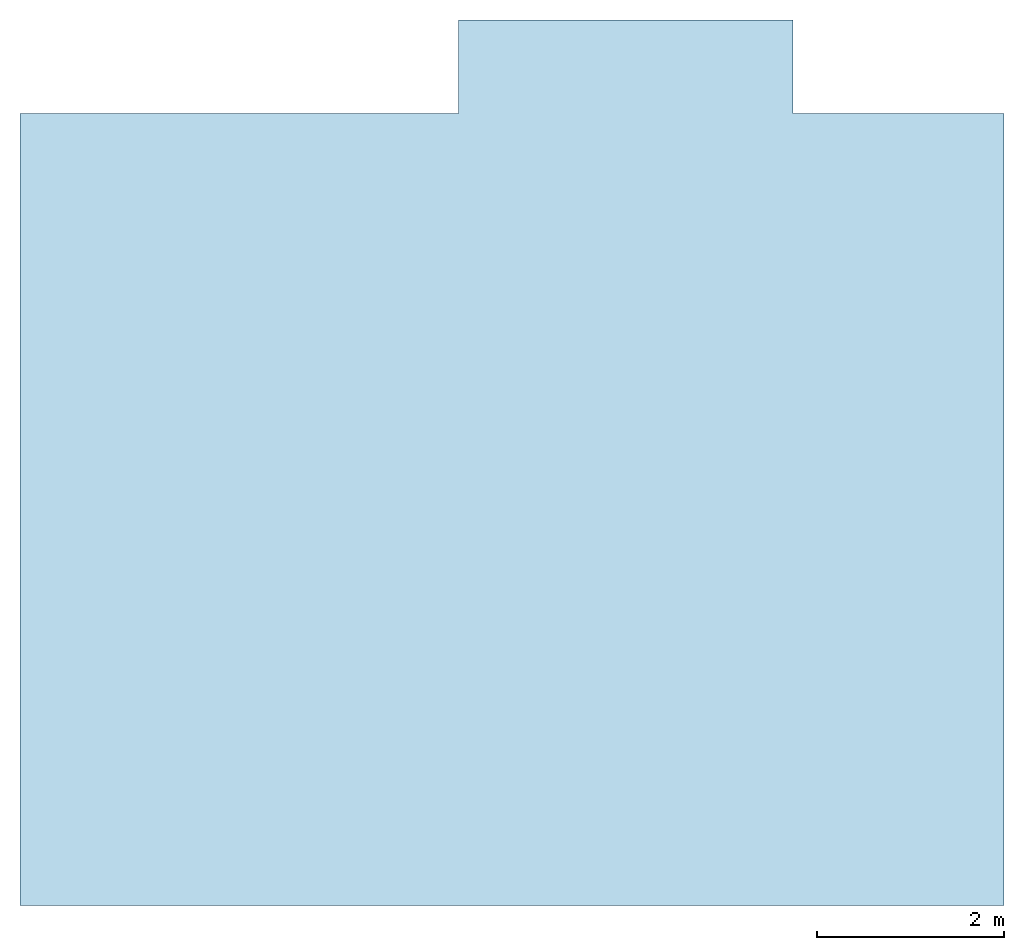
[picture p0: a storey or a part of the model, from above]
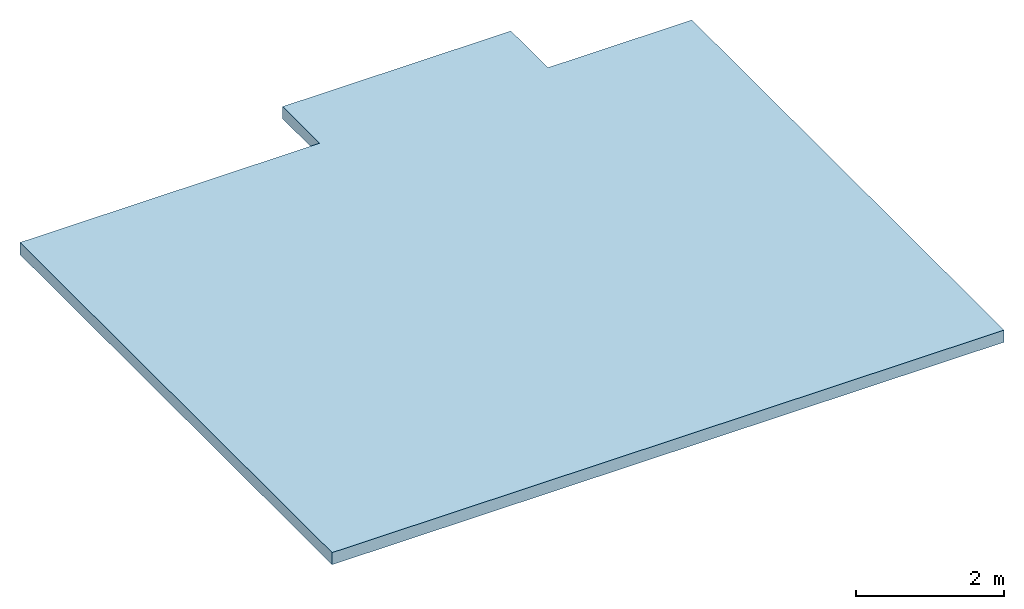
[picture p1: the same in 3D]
Properties of the parts of a building model (IFC2X3), part 6 of 6

# IfcWindow: Janela Multi-Caixilho Vertical 27 (3)
BaseQuantities - GrossArea: 0.64 m2; Height: 800 mm; Width: 800 mm; Perimeter: 3200 mm; Area: 0.64 m2; Volume: 0.0181695 m3; Depth: 160 mm; NetVolume: 0.0181695 m3
ArchiCADQuantities - Abertura Volume de Vão L/D: 0.10444 m3; P/J Volume Nominal da Abertura: 0.1024 m3; Abertura Área da Superfície L/D: 2.73291 m2; P/J Área de Superfície Nominal do Vão: 0.64 m2; P/J Largura do Vão no Lado Oposto do Requadro: 800 mm; P/J Altura do Vão no Lado Oposto do Requadro: 830 mm; P/J Largura do Vão no Lado do Requadro: 800 mm; P/J Altura do Vão no Lado do Requadro: 800 mm; Área da Superfície da Abertura no Lado do Requadro da J/P: 0.664 m2; Área da Superfície da Abertura no Lado Oposto ao Requadro da J/P: 0.64 m2; P/J Largura do Vão Nominal no Lado Oposto do Requadro: 800 mm; P/J Altura do Vão Nominal no Lado Oposto do Requadro: 800 mm; P/J Largura do Vão Nominal no Lado do Requadro: 800 mm; P/J Altura do Vão Nominal no Lado do Requadro: 800 mm; P/J Área da Superfície do Vão Nominal no Lado do Requadro: 0.64 m2; P/J Área da Superfície do Vão Nominal no Lado Oposto do Requadro: 0.64 m2; Altura da Soleira/Peitoril ou Padieira: 1400 mm; P/J Altura Nominal do Parapeito: 1400 mm; P/J Altura do Parapeito no Lado do Requadro: 1400 mm; P/J Altura do Parapeito no Lado Oposto do Requadro: 1400 mm; P/J Altura Nominal da Padieira: 2200 mm; P/J Altura da Padiera no Lado Oposto do Requadro: 2200 mm; P/J Altura da Padiera no Lado do Requadro: 2200 mm; Espessura da Parede: 160 mm; Espessura do Batente: 50 mm; Altura: 800 mm; Volume (Líquido): 0.0181695 m3; Largura: 800 mm; Elevação à Origem do Projeto: 1400 mm; Elevação ao 1º Nível de Referência: 1400 mm; Elevação ao 2º Nível de Referência: 1400 mm; Elevação ao Nível do Mar: 1400 mm; Elevação ao Piso: 1400 mm; Afastamento do Piso de Origem: 1400 mm; Área da Superfície: 2.73291 m2; Elevação do Topo ao Primeiro Nível de Referência: 2200 mm; Elevação do Topo Ao Piso de Origem: 2200 mm; Elevação do Topo À Cota Zero: 2200 mm; Elevação do Topo Ao Nível do Mar: 2200 mm; Elevação do Topo Ao Segundo Nível de Referência: 2200 mm; Elevação da Base Ao Primeiro Nível de Referência: 1370 mm; Elevação da Base Ao Piso de Origem: 1370 mm; Elevação da Base À Cota Zero: 1370 mm; Elevação da Base Ao Nível do Mar: 1370 mm; Elevação da Base Ao Segundo Nível de Referência: 1370 mm; Área da Superfície da Base (Líquida): 2.73291 m2
AC_Equantity_Janela_Multi-Caixilho_Vertical_27 - Largura: 800 mm; Altura: 800 mm; Dimensão Z: 1000 mm; Nível da Base: 1000 mm; Nível do Topo: 0 mm; Altura Peitoril ao Piso Atual: 1400 mm; Abertura para o Núcleo da Parede: 50 mm; Nova Largura Direita da Trama de Parede: 150 mm; Nova Largura Esquerda da Trama de Parede: 150 mm; Espessura Parede Ligação: 0 mm; Espessura Parede 2 Conectada: 160 mm; Espessura Parede 1 Conectada: 160 mm; Largura Pilar de Canto: 0 mm; Espessura Pilar Canto: 0 mm; Projeção Pilar de Canto: 0 mm; Tolerância Máxima: 100 mm; Tolerância: 0 mm; Tolerância Esquerda: 0 mm; Tolerância Direita: 0 mm; Tolerância Superior: 0 mm; Tolerância Inferior: 0 mm; Largura de Vão: 800 mm; Altura de Vão: 800 mm; Largura Face de Vão: 800 mm; Altura Face de Vão: 800 mm; Largura Unidade: 800 mm; Altura Unidade: 800 mm; Distância Eixo: 800 mm; Altura Painel 1: 212.5 mm; Altura Painel 2: 187.5 mm; Altura Painel 3: 187.5 mm; Altura Painel 4: 212.5 mm; Altura Painel 5: 256 mm; Altura Painel 6: 500 mm; Altura Painel 7: 500 mm; Altura Painel 8: 500 mm; Altura Painel 9: 500 mm; Altura do Painel Restante: 307 mm; Espessura Batente: 50 mm; Largura Batente: 50 mm; Largura Batente Lado 2: 47 mm; Largura Batente Cimo: 47 mm; Largura Batente Base: 47 mm; Profundidade Rebaixo: 20 mm; Largura Rebaixo: 20 mm; Largura Bandeira centro: 80 mm; Largura Bandeira 1: 100 mm; Largura Bandeira 2: 100 mm; Largura Bandeira 3: 100 mm; Largura Bandeira 4: 100 mm; Largura Bandeira 5: 100 mm; Largura Bandeira 6: 100 mm; Largura Bandeira 7: 100 mm; Largura Bandeira 8: 100 mm; Largura Bandeira 9: 100 mm; Altura das Divisões Horizontais do Caixilho 1: 117.5 mm; Altura das Divisões Horizontais do Caixilho 2: 117.5 mm; Altura das Divisões Horizontais do Caixilho 3: 117.5 mm; Altura das Divisões Horizontais do Caixilho 4: 117.5 mm; Altura das Divisões Horizontais do Caixilho 5: 176 mm; Altura das Divisões Horizontais do Caixilho 6: 900 mm; Altura das Divisões Horizontais do Caixilho 7: 900 mm; Altura das Divisões Horizontais do Caixilho 8: 900 mm; Altura das Divisões Horizontais do Caixilho 9: 900 mm; Altura das Divisões Horizontais do Caixilho 10: 900 mm; Espessura Estrutura Caixilho: 20 mm; Largura Caixilho: 50 mm; Largura Grelha: 20 mm; Espessura Grelha: 25 mm; Espessura Vidro: 20 mm; Espessura Venezianas: 10 mm; Largura Venezianas: 50 mm; Sobred. Abertura Esquerda: 0 mm; Sobred. Direita Abertura: 0 mm; Sobred. Topo Abertura: 0 mm; Sobred. Base Abertura: 0 mm; Largura Arquitrave Principal: 20 mm; Largura Lado 1 (gs_tw_right_out): 100 mm; Largura Lado 2 (gs_tw_left_out): 100 mm; Largura Topo (gs_tw_top_out): 100 mm; Largura Inferior (gs_tw_bottom_out): 100 mm; Espessura de Parede (gs_trim_thk_out): 25 mm; Espessura na Abertura da Parede (gs_trim_width_out): 25 mm; Paralelas (gs_trim_offs_out): 0 mm; Bordo (gs_trim_jambext_nosing_out): 50 mm; Saliência Superior (gs_trimov_top_left_out): 0 mm; Saliência Superior (gs_trimov_top_right_out): 0 mm; Ressalto Inferior (gs_trimov_bot_left_out): 0 mm; Ressalto Inferior (gs_trimov_bot_right_out): 0 mm; Ressalto Inferior (casingOverhangBottomSideOut): 50 mm; Largura Lado 1 (gs_tw_right_in): 100 mm; Largura Lado 2 (gs_tw_left_in): 100 mm; Largura Topo (gs_tw_top_in): 100 mm; Largura Inferior (gs_tw_bottom_in): 100 mm; Espessura de Parede (gs_trim_thk_in): 25 mm; Espessura na Abertura da Parede (gs_trim_width_in): 25 mm; Paralelas (gs_trim_offs_in): 0 mm; Bordo (gs_trim_jambext_nosing_in): 50 mm; Saliência Superior (gs_trimov_top_left_in): 0 mm; Saliência Superior (gs_trimov_top_right_in): 0 mm; Ressalto Inferior (gs_trimov_bot_left_in): 0 mm; Ressalto Inferior (gs_trimov_bot_right_in): 0 mm; Largura Peitoril: 105 mm; Largura Topo Parapeito: 10 mm; Altura Topo Peitoril: 10 mm; Espessura Peitoril: 30 mm; Espessura Lateral da Frente Peitoril: 15 mm; Elevação Peitoril: 5 mm; Recobrimento Goteira Peitoril: 20 mm; Largura Goteira Peitoril: 30 mm; Testeira Peitoril: 20 mm; Avanço do Parapeito Esquerda: 0 mm; Avanço do Parapeito Direita: 0 mm; Inclinação do Parapeito: 35 mm; Inclin. Peitoril da Parede: 0 mm; Profund. Vão Posterior (gs_sill_holeDepthBehind): 0 mm; Espessura do Tijolo (gs_brick_sill_br_thk): 65 mm; Espessura de Argamassa (gs_brick_sill_mort_thk): 15 mm; Largura Peitoril Int.: 90 mm; Espessura Peitoril Int.: 25 mm; Peitoril Int. Arredondado: 30 mm; Saliência Esq. Peitoril Int.: 0 mm; Saliência Dir. Peitoril Int.: 0 mm; Inclinação do Parapeito Int.: 0 mm; Altura Perfil: 65 mm; Espessura Perfil: 110 mm; Altura Painel: 1500 mm; Afast. Interior: 20 mm; Profund. Fechamento: 0 mm; Largura Batente Extra: 40 mm; Espess. Batente Extra: 30 mm; Largura Barra:: 30 mm; Comprim. Vara Suspensa: 20 mm; Raio Vara Suspensa: 5 mm; Distância Painel: 6 mm; Saliência Exterior: 0 mm; Largura Painel Interior: 120 mm; Comprim. Abertura 3D: 1500 mm; Comprim. Fechado 3D: 0 mm; Comprimento 1 Abertura 3D (gs_shutter_opLength_1): 560 mm; Comprimento 1 Abertura 3D (gs_shutter_opLength_2): 140 mm; Altura Abertura 3D: 1500 mm; Altura Fechado 3D: 0 mm; Espessura Painel: 50 mm; Largura Estrutura Painel: 50 mm; Largura Moldura Inferior: 50 mm; Largura Painel: 0 mm; Espess. de Enchimento de Painel: 10 mm; Espessura da Veneziana: 10 mm; Largura Grelha Ventilação: 40 mm; Largura Divisor Moldura Horiz.: 50 mm; Largura de Divisor Moldura Vert.: 50 mm; Raio do Vão: 10 mm; Largura Bordo Vertical: 100 mm; Largura Estrutura Z: 50 mm; Espessura Estrutura Z: 25 mm; Espess. Placas Verticais: 25 mm; Espess. Placas Horizontais: 25 mm; Largura Aprox. Placas Verticais: 80 mm; Largura Aprox. Placas Horizontais: 115 mm; Altura Caixa (gs_shutRoll_boxHeight): 200 mm; Profund. Caixa (gs_shutRoll_boxWidth): 150 mm; Afast. Caixa Esq.: 0 mm; Afast. Caixa Dir.: 0 mm; Profund. Anteparos: 72.5 mm; Distância da Parede (gs_shutRoll_distFromWall): 0 mm; Distância da Padieira (gs_shutRoll_distFromHead): 0 mm; Largura da Ripa: 50 mm; Altura Caixa (gs_shutLam_boxHeight): 200 mm; Profund. Caixa (gs_shutLam_boxWidth): 150 mm; Largura Capa: 0 mm; Distância da Parede (gs_shutLam_distFromWall): 0 mm; Distância da Padieira (gs_shutLam_distFromHead): 0 mm; Largura Segmento (gs_shutLam_segmentWidth): 60 mm; Altura Caixa (gs_shutLam2_boxHeight): 60 mm; Largura Caixa: 60 mm; Distância da Janela: 60 mm; Distância da Padieira (gs_shutLam2_distFromHead): 60 mm; Altura do Eixo da Caixa da Padieira: 0 mm; Largura Segmento (gs_shutLam2_segmentWidth): 60 mm; Distância entre Arco e Janela: 0 mm; Avanço à Esquerda do Arco de Alvenaria: 0 mm; Avanço à Direita do Arco de Alvenaria: 0 mm; Espelho do Arco de Alvenaria: 30 mm; Projeção do Arco de Alvenaria: 0 mm; Altura do Arco de Alvenaria: 250 mm; Profundidade do Arco de Alvenaria: 120 mm; Profund. Vão Posterior (gs_masonry_arch_rearHoleDepth): 0 mm; Espessura do Tijolo (gs_masonry_arch_brick_thk): 65 mm; Espessura de Argamassa (gs_masonry_arch_mort_thk): 10 mm; Largura Fecho: 100 mm; Sobredimensão Fecho: 0 mm; Projeção Fecho: 10 mm; Profund. Face de Vão (gs_wido_sill): 50 mm; Profund. Face de Vão (AC_wido_sill): 50 mm; Profund. Ombreira Lado 2: 60 mm; Profund. Ombreira: 60 mm; Profund. Ombreira Interior Lado 2 (gs_reveal_splayed_innerLeft): 60 mm; Profund. Ombreira Interior (gs_reveal_splayed_innerRight): 60 mm; Profund. Ombreira Interior Lado 2 (gs_reveal_double_innerLeft): 60 mm; Profund. Ombreira Interior (gs_reveal_double_innerRight): 60 mm; Profund. Batente Cima: 60 mm; Profund. Batente Peitoril: 60 mm; Profundidade Padieira Interior (gs_reveal_splayed_innerTop): 60 mm; Profundidade Peitoril Interior (gs_reveal_splayed_innerBottom): 60 mm; Profundidade Padieira Interior (gs_reveal_double_innerTop): 60 mm; Profundidade Peitoril Interior (gs_reveal_double_innerBottom): 0 mm; Profund. Batente Exterior: 80 mm; Limite Espess. Reboco: 40 mm; Distância de Camada do Encerram.: 0 mm; Largura do Fecho: 38 mm; Espessura do Fecho: 100 mm; Espessura da Camada: 25 mm; Espessura do Perfil: 75 mm; Espessura Personal.: 15 mm; Saliência Camada para Espess. Batente: 0 mm; Profundidade do Recorte: 50 mm; Largura de Parapeito: 1000 mm; Avanço Lateral 1: 0 mm; Avanço Lateral 2: 0 mm; Altura Parapeito: 900 mm; Ressalto Inferior (gs_parapet_botelev): 0 mm; Distância Abertura 1 Caixilho 1: 0 mm; Distância Abertura 2 Caixilho 1: 0 mm; Distância Abertura 1 Caixilho 2: 0 mm; Distância Abertura 2 Caixilho 2: 0 mm; Distância Abertura 1 Caixilho 3: 0 mm; Distância Abertura 2 Caixilho 3: 0 mm; Distância Abertura 1 Caixilho 4: 0 mm; Distância Abertura 2 Caixilho 4: 0 mm; Distância Abertura 1 Caixilho 5: 0 mm; Distância Abertura 2 Caixilho 5: 0 mm; Distância Abertura 1 Caixilho 6: 0 mm; Distância Abertura 2 Caixilho 6: 0 mm; Distância Abertura 1 Caixilho 7: 0 mm; Distância Abertura 2 Caixilho 7: 0 mm; Distância Abertura 1 Caixilho 8: 0 mm; Distância Abertura 2 Caixilho 8: 0 mm; Distância Abertura 1 Caixilho 9: 0 mm; Distância Abertura 2 Caixilho 9: 0 mm; Distância Abertura 1 Caixilho 10: 0 mm; Distância Abertura 2 Caixilho 10: 0 mm; Comprimento Abertura em 2D: 0 mm; Sobred. Abertura Esq. AC: 0 mm; Sobred. Abertura Dir. AC: 0 mm; Sobred. Padieira AC: 0 mm; Sobred. Abertura Base AC: 0 mm
Component Quantities - Component, Volume Componente (Líquido): 0.0181695 m3; Component, Volume do componente (Bruto): 0.0181695 m3
Name | ID do Elemento = ID do Elemento e Associação | Nome da Zona Relacionada = Da Zona | Número da Zona Relacionada = Do Número de Zona
J06 | J06 | Banheiro 1 | 03
J07 | J07 | Banheiro 2 | 03
J01 | J01 | Cozinha | 05 | ArchiCADProperties - Até Zona: Cozinha; Até Número de Zona: 05

# IfcWindow: Janela de Correr 3-Caixilhos 27 (3)
In: Pavimento Térreo
Type - OperationType: USERDEFINED; ParameterTakesPrecedence: no; Sizeable: no
Description: Janela-externa-genérico-aço_inox-correr-100cm x 120cm; OverallHeight: 1200 mm; OverallWidth: 1000 mm; Classification: 3E 20 04 02 02 Janela de correr (NBR 15965-5 3E); Janela (Classificação Archicad)
Pset_WindowCommon - ThermalTransmittance: 0; GlazingAreaFraction: 0.649067; IsExternal: yes
AC_Pset_Janela_de_Correr_3-Caixilhos_27 - Contornos Parede (0-Nenhum,1-Completo,2-Lado,3-Comprimento): 0; Pontos-Quentes 0-Nenhum,1-2D,2-3D,3-Todos: 3; Opção de Visualização em Planta: 3; Ângulo de Posição da Abertura: 0 deg; Furo tem Superfície Lateral Parede: yes; Furos em Divisão de Superfícies são Curvos em Paredes Curvas: no; Mostrar Pontos-Quentes 2D em 3D: yes; Tipo de Parede: 1; Tipo de Direção de Parede: 0; Posição de Ancoragem da Abertura: 1; Função de correção de erros de Janela de canto: no; Tipo de Posicionamento (1=CW,0=W): no; Corda: no; Demolição / Nova Construção: 1; Novo Tipo de Trama de Parede: Bloco; Nova Caneta de Trama de Parede: Geral - Geral; Nova Caneta de Fundo de Trama de Parede: Fundos - Cor 1; Mostrar nova construção na Parede: no; Tipo de linha de demolição: 4; Mostrar parâmetro Demolição / Novo: no; Função Janela de Canto: yes; Ângulo de Canto: 90 deg; Espess. Dif. Parede Conexão: no; Pilar de Canto: no; Canto 2: no; Ângulo do Canto 2: 90 deg; Dif. Conexões de Espessura Parede 2: no; Canto 1: no; Ângulo do Canto 1: 90 deg; Dif. Conexões de Espessura Parede 1: no; Tipo de Conexão 1 do Canto: 1; Tipo de Conexão 2 do Canto: 1; Inteiramente Editável: yes; 2D: 1; Mostrar Face de Vão em Símbolo: 1; 3D: 8; Tamanho Nominal: 0; Definir Tamanho de Vão como Tamanho Nominal: yes; Definir Tamanho de Reentrância como Tamanho Nominal: no; Definir Tamanho de Unidade como Tamanho Nominal: no; Transferir Tamanho Nominal Atual para Seleção: no; Largura Uniforme Batente: no; Tipo de Travessa: 0; Bandeira Superior: no; Configuração de Paineis: 1; Direção do Vidro Fixo (FixGlassDir): Pela Direção da Abertura; Direção do Vidro Fixo (FixGlassDir_m): 1; Tipo Abertura Caixilhos Principais: 1; Tipo de Abertura Caixilhos Principais Bandeira: 1; Tipo de Abertura Caixilhos Laterais Bandeira: 1; Caixilhos Uniformes: no; Tipo Caixilho (iMullionStyle_00): 1; Tipo Caixilho (iMullionStyle_01): 2; Tipo Caixilho (iMullionStyle_03): 1; Tipo Caixilho (iMullionStyle_04): 15; Tipo Caixilho (iMullionStyle_05): 1; Tipo Caixilho (iMullionStyle_07): 1; Tipo Caixilho (iMullionStyle_08): 1; Editar Ponto-quente Grelha: yes; Posição Grelha: 3; Saliência: no; Maçaneta Abertura (gs_handle_type): Nenhum; Maçaneta Abertura (gs_handle_type_m): 0; Guarnição Externa: no; Tipo Guarnição Externa (gs_trimtype_out): Simples; Tipo Guarnição Externa (gs_trimtype_out_int): 1; Tipo de Travessa Guarnição Externa: 1; Arquitrave Principal: yes; Tipo Arquitrave Principal: 1; Guarnição Externa Inferior: yes; Guarnição/Alizar na Superfície Externa da Parede: yes; Larguras Uniformes da Guarnição (gs_trim_outside_uniform): yes; Guarnição Interna: no; Tipo Guarnição Interna (gs_trimtype_in): Simples; Tipo Guarnição Interna (gs_trimtype_in_int): 1; Guarnição/Alizar na Superfície Interna da Parede: yes; Larguras Uniformes da Guarnição (gs_trim_inside_uniform): yes; Soleira/Peitoril (gs_sill_outside): no; Sobredim. Peitoril: no; Tipo de Parapeito Exterior: 1; Ângulo Peitoril: 3 deg; Parapeito Curvo em Paredes Curvas: yes; Isolamento abaixo do Peitoril: yes; Usar Camada Isolamento de Parede: no; Nível Detalhe 3D Peitoril Tijolo: 1; Peitoril Interno (gs_board_inside): no; Ângulo Peitoril Int.: 0 deg; Peitoril Int. Curvado em Paredes Curvas: yes; Peitoril Int. em Paredes Poligonais: 1; Ventilação Natural: no; Tipo Ventilação Natural: 2; Caixilho Principal 1: no; Caixilho Principal 2: no; Principal Caixilho 3: no; Caixilho Bandeira 1: yes; Caixilho Bandeira 2: yes; Bandeira Caixilho 3: yes; Quebra-Sol: no; Tipo Quebra-Sol: 1; Tipos de Quebra-Sol Ativados: 126; Número de Paineis: 2; Número de Paineis 2: 1; Posição Painel (gs_shutter_panelPos): Simétrico; Posição Painel (gs_shutter_iPanelPos): 1; Altura Automática Veneziana: yes; Batente Extra: no; Tipo Cobertura (gs_slidingShutter_cover): Perfil-Z; Tipo Cobertura (gs_slidingShutter_iCover): 1; Direção de Empilham. (gs_foldingShutter_stacking): Interno; Direção de Empilham. (gs_foldingShutter_iStacking): 1; Abrir em 3D: yes; Ângulo de abertura 3D: 180 deg; Mostrar Símbolo 2D: yes; Mostrar Linhas de Abertura no Símbolo: no; Tipo Painel (gs_shutPanel_type): Estilo 1; Tipo Painel (gs_shutPanel_iType): 1; Largura Base Batente Diferente: no; Largura Automática Veneziana: yes; Ângulo Grelha Ventilação: 30 deg; Nº Vãos Horiz.: 5; Nº Vãos Vert.: 8; Posição Rolamento Veneziana (gs_shutRoll_placement): Na Fachada; Posição Rolamento Veneziana (gs_shutRoll_iPlacement): 1; Tipo Caixa (gs_shutRoll_boxType): Retangular; Tipo Caixa (gs_shutRoll_iBoxType): 1; Posição Grade (gs_shutRoll_railPos): Em Guarnição; Posição Grade (gs_shutRoll_iRailPos): 1; Mostrar Guarnição Atrás do Quebra-Sol (gs_shutRoll_showCasingBehind): no; Isolamento Atrás da Caixa (gs_shutRoll_cutWallBehind): no; Incluir Altura na Altura do Vão da Parede: no; Ângulo de Topo da Caixa: 10 deg; Largura Caixa Original (gs_shutRoll_boxDefaultSize): Largura Face de Vão; Largura Caixa Original (gs_shutRoll_iBoxDefaultSize): 1; Colocação Persianas (gs_shutLam_placement): Fixada na Fachada; Colocação Persianas (gs_shutLam_iPlacement): 1; Isolamento Atrás da Caixa (gs_shutLam_cutWallBehind): no; Caixa Aberta: yes; Trilho: yes; Posição Grade (gs_shutLam_railPos): Em Guarnição; Posição Grade (gs_shutLam_iRailPos): 1; Mostrar Guarnição Atrás do Quebra-Sol (gs_shutLam_showCasingBehind): no; Ângulo Rotação das Lamelas (gs_shutLam_rotation): 45 deg; Ângulo Rotação das Lamelas (gs_shutLam2_rotation): 45 deg; Arco de Alvenaria (bMasonryArch): no; Arco de Alvenaria (gs_masonry_arch_int): 2; Tipo de Arco de Alvenaria (gs_masonry_arch_structure): Arco de Reboco; Tipo de Arco de Alvenaria (gs_masonry_arch_structure_int): 1; Arco no Topo: yes; Nicho abaixo do Arco: yes; Ângulo de Plano do Arco: 75 deg; Superfícies dos Nichos Personalizados: no; Tipo de Requadro (gs_reveal_type_new): Requadro Reto - Borda; Tipo de Requadro (gs_reveal_type_int): 1; Tipo de Requadro Base (gs_reveal_type_bottom): Requadro Reto; Tipo de Requadro Base (gs_reveal_type_bottom_int): 2; Tipo de Requadro Exterior: Requadro Reto; Tipo de Requadro (gs_reveal_doubleOuterTypeInt): 0; Tipo de Requadro Interior: Requadro Reto; Tipo de Requadro (gs_reveal_doubleInnerTypeInt): 0; Profundidade Uniforme: yes; Ângulo Lado 2: 20 deg; Ângulo Lado: 20 deg; Ângulo do Topo: 20 deg; Ângulo da Base: 20 deg; Usar Componente de Acabamento: no; Auto Ligagem da Face Interna da Argamassa: yes; Ligar Face Interna da Argamassa: 0; Auto Ligagem da face Externa da Argamassa: yes; Ligar Face Externa da Argamassa: 0; Dimensionável em 2D: no; Mostrar em 3D: no; Tipo de Fechamento (gs_closure_type): Sem Fechamento; Tipo de Fechamento (gs_closure_type_int): 1; Dobrar Camada no Lado (gs_cavity_side): Ambas; Dobrar Camada no Lado (iCavityClosureSide): 1; No. de Camadas: 1; Numerar a partir de (gs_nTurnDir): Face externa; Numerar a partir de (iCavityClosureTurnDir): 1; Colocar Fechamento no Lado 2: yes; Colocar Fechamento no Lado 1: yes; Colocar Fechamento no Topo: no; Colocar Fechamento na Base: no; Colocar Fechamento para Camada: 1; Colocar Fechamento do Lado (gs_cc_dutch_ClosureToSide): 1; Fenda na Camada Externa: yes; Dobrar Camada para Encerram.: no; Inserir Camada de Isolamento: yes; Mostrar Camada de Isolamento: yes; Caneta de Contorno (gs_penJoint): Aberturas - Corte Não Estrutural; Tipo Linha Contorno (gs_ltJoint): 1; Tipo de Trama (gs_fillJoint): Isolamento 2; Caneta da Trama (gs_penJointFg): Geral - Geral; Caneta do Fundo da Trama (gs_penJointBg): Elementos 2D - Desenhos; Superfície Personalizada: no; Superfície: Madeira - Pinho Granulado Horizontal; Caneta de Contorno (gs_penPlug): Aberturas - Corte Não Estrutural; Tipo Linha Contorno (gs_ltPlug): 1; Tipo de Trama (gs_fillPlug): Isolamento 2; Caneta da Trama (gs_penPlugFg): Geral - Geral; Caneta do Fundo da Trama (gs_penPlugBg): Elementos 2D - Desenhos; Lado Ombreira Editado: 1; Lado Parede Editado: 1; Número de Camada Editado: 1; Camada que Dobra: no; Considerar Camada como Reboco: no; Espessura da Camada que Dobra: 1; Orientação Trama: 1; Linha Separa Camada que Dobra: no; Caneta Linha Separação: Geral - Geral; Último Lado Selecionado: no; Método de Fechamento Alterado Automaticamente: no; Conexão à Esquerda: no; Conexão à Direita: no; Conexão em Cima: no; Conexão em Baixo: no; Recorte na Parede: no; Tamanhos da Inserção na Parede (gs_parapet_sizes_st): Automático; Tamanhos da Inserção na Parede (iParapetSize): 1; Dimensões Autom. de Largura e Altura: yes; Inserção de Parede Embaixo a (gs_parapet_bottom_st): Piso Atual; Inserção de Parede Embaixo a (iParapetBottom): 1; Mostrar Parapeito Escondido: yes; Tipo Linha Peitoril Escondido: 1; Ângulo de Abertura Caixilho Superior (openingAngle_05): 0 deg; Ângulo de Abertura Caixilho Superior (openingAngle2_05): 0 deg; Ângulo de Abertura Caixilho Superior (openingAngle_06): 0 deg; Ângulo de Abertura Caixilho Superior (openingAngle2_06): 0 deg; Ângulo Abertura de Caixilho Lado Superior (openingAngle_07): 0 deg; Ângulo Abertura de Caixilho Lado Superior (openingAngle2_07): 0 deg; Ângulo Abertura de Caixilho Lado Superior (openingAngle_08): 0 deg; Ângulo Abertura de Caixilho Lado Superior (openingAngle2_08): 0 deg; Substituir OVM para Visual. Simbólica 2D: no; Tipo Linha Abertura: 1; Forma da Linha de Abertura (or_SwingType): Curva; Forma da Linha de Abertura (or_iSwingType): 1; Forma da Linha de Abertura (or_SlidingType): Nenhum; Forma da Linha de Abertura (or_iSlidingType): 0; Caneta de Linha de Abertura (or_opLinePen): Aberturas - Geral; Caneta de Linha de Abertura (or_iOpLinePen): 3; Substituir OVM para Projeções 3D: no; Mostrar Linha de Abertura: yes; Tipo Linha Lado da Abertura (or_opLineType3dIn): Linha Sólida; Tipo Linha Lado da Abertura (or_iOpLineType3dIn): 0; Tipo Linha Lado Oposto (or_opLineType3dOut): Linha Sólida; Tipo Linha Lado Oposto (or_iOpLineType3dOut): 0; Orientação da Linha (or_oplineStyle): Maçaneta; Orientação da Linha (or_iOplineStyle): 1; Caneta de Linha em Vista: Aberturas - Geral; Caneta da Linha em Corte: Aberturas - Moldura; Caneta de Linha em Corte em Ambos os Lados da Guarnição: Aberturas - Geral; Linha Contorno Parede (gs_wcont_line): Ambos Lados; Linha Contorno Parede (iWallContourLine): 4; Tipo de Linha Interior Contorno Parede: 1; Tipo de Linha Exterior Contorno Parede: 1; Linha Interna Tracejada de Projeção Parede: 4; Linha Externa Tracejada de Projeção Parede: 4; Caneta Linha Contorno Parede: Aberturas - Geral; Tramas Usadas: yes; Tipo Trama Batente: Trama Vazia; Caneta Trama Batente: Aberturas - Fundo de Trama; Caneta Fundo Trama Batente: Fundos - Cor 1; Tipo de Trama Caixilho: Ar (Vazio); Caneta da Trama Caixilho: Aberturas - Fundo de Trama; Caneta da Trama de Fundo Divisões Interiores: Fundos - Cor 1; Tipo de Trama de Não-Cortado: Trama Vazia; Caneta da Trama de Não-Cortado: Aberturas - Fundo de Trama; Caneta de Fundo da Trama Não-Cortado: Fundos - Cor 1; Tipo Trama Símbolo em Planta: Trama Vazia; Caneta Trama para Símb. em Planta: Fundos - Cor 1; Caneta Fundo para Simb. em Planta: Fundos - Cor 1; Caneta de Vista e 3D da Peitoril: Geral - Geral; Caneta de Contorno de Corte Peitoril: Geral - Geral; Tipo de Trama Corte Peitoril: Ar (Vazio); Caneta Trama do Parapeito em Corte: Fundos - Cor 1; Caneta Trama de Fundo do Parapeito em Corte: Fundos - Cor 1; Caneta de Contorno Isolamento Seção: Geral - Geral; Tipo de Trama do Isolamento da Seção: Isolamento 2; Caneta Trama Isolamento Seção: Geral - Geral; Caneta da Trama de Fundo Isolamento Seção: Fundos - Cor 1; Caneta de Vista e 3D do Peitoril Interno: Geral - Geral; Caneta de Contorno Seção Peitoril Interno: Geral - Geral; Tipo de Trama do Peitoril Interno em Corte: Ar (Vazio); Caneta Trama do Peitoril Interno em Corte: Fundos - Cor 1; Caneta Trama de Fundo do Peitoril Interno em Corte: Fundos - Cor 1; Tipo de Trama de Guarnição Int.: Ar (Vazio); Caneta de Trama de Guarnição Int: Fundos - Cor 1; Caneta de Fundo de Trama de Guarnição Int: Fundos - Cor 1; Tipo de Trama de Guarnição Ext: Ar (Vazio); Caneta de Trama de Guarnição Ext: Fundos - Cor 1; Caneta de Fundo de Trama de Guarnição Ext: Fundos - Cor 1; Tipo de Trama de Seção do Arco: Trama Vazia; Caneta da Trama da Seção do Arco: Fundos - Cor 1; Caneta de Fundo de Trama de Seção do Arco: Fundos - Cor 1; Tipo de Trama do Corte do Perfil da Ventilação: Ar (Vazio); Caneta da Trama do Corte do Perfil da Ventilação: Fundos - Cor 1; Caneta do Fundo da Trama do Corte do Perfil da Ventilação: Fundos - Cor 1; Tipo de Linha de Símbolo Quebra-Sol: 1; Caneta da Linha em Corte do Quebra-Sol: Geral - Geral; 3D/Caneta das Linhas não Cortadas no Corte: Geral - Geral; Tipo da Trama de Corte Quebra-Sol (gs_sunShade_cutFillType): Trama Vazia; Tipo da Trama de Corte Quebra-Sol (gs_sunShade_cutFillPen): Geral - Geral; Caneta da Trama do Fundo Corte Quebra-Sol: Fundo da Janela; Tipo Trama Isolamento Quebra-Sol: Isolamento 1; Caneta da Trama Isolamento Quebra-Sol: Geral - Geral; Caneta do Fundo Isolamento Quebra-Sol: Fundo da Janela; Junção Elementos Batente: 2; Caneta Moldura: Aberturas - Geral; Caneta Caixilho: Aberturas - Geral; Caneta Vidro: Aberturas - Corte Não Estrutural; Caneta de Arco de Alvenaria: Paredes - Geral; Sombra: yes; Superfícies Uniformes Janela: yes; Batente Externo: Metal - Aço Inoxidável; Batente Interno: Metal - Aço Inoxidável; Caixilho Externo: Metal - Aço Inoxidável; Caixilho Interno: Metal - Aço Inoxidável; Superfície Saliência Externa: Metal - Aço Inoxidável; Superfície Saliência Interna: Metal - Aço Inoxidável; Superfície Maçaneta: Metal - Aço Inoxidável; Superfície Acessórios Maçaneta: Metal - Ferro; Vidro: Vidro - Simples; Grelha Externa: Metal - Aço Inoxidável; Grelha Interna: Metal - Aço Inoxidável; Painel Sólido Exterior: Metal - Aço Inoxidável; Painel Sólido Interior: Metal - Aço Inoxidável; Superfícies Guarnição Uniformes: yes; Interior Guarnição: Madeira - Pinho Granulado Horizontal; Exterior Guarnição: Madeira - Pinho Granulado Horizontal; Perfil de Ventilação: Metal - Alumínio; Painel Veneziana: Madeira - Pinho Granulado Horizontal; Moldura Painel Veneziana: Madeira - Pinho Granulado Horizontal; Caixa do Rolamento Veneziana: Metal - Aço Inoxidável; Lâminas Rolamento Veneziana: Pintura - Branco Titânio; Barras Rolamento Veneziana: Pintura - Branco Titânio; Caixa Persianas: Metal - Aço Inoxidável; Segmento Persianas: Pintura - Branco Titânio; Trilho Deslizante Veneziana: Metal - Aço Inoxidável; Soleira/Peitoril (gs_sill_mat): Madeira - Pinho Granulado Horizontal; Argamassa do Peitoril em Tijolo: Estuque - Branco Áspera; Peitoril Interno (gs_board_mat): Madeira - Pinho Granulado Horizontal; Arco de Alvenaria em Tijolo: Tijolo - Aparelho ao Comprido; Argamassa do Arco de Alvenaria: Estuque - Branco Áspera; Fecho Arco de Alvenaria: Pedra - Arenito 01; Nincho: Pintura - Óxido de Chumbo Amarelo; Superfície de Pilar de Canto: Madeira - Pinho Granulado Horizontal; Direção da Abertura: 0; Visualizar como Travessa: no; Caneta Linha Fim Parede: Geral - Geral; Tipo de Linha Fim de Parede: 4; Profundidade Travessa em Símbolo: no; Tipo de Linha do Símbolo da Profundidade Travessa: 4; Caneta do Símbolo da Profundidade Travessa: Texto - Geral; Janela pertence à Zona dentro da qual abre: no; Custo: 0; Área Total Envidraçada (gs_list_glassarea_tmp): 0; Substituir Área Envidraçada: no; Área Total Envidraçada (gs_list_glassarea): 0.649067; Perimetro Total Vidro: 0; Desempenho Ar Livre (mm2/l/m): 0; Tipo de Grupo (FM_Type): Objetos padrão; Tipo de Grupo (iFMType): 1; Peso Objeto: 0; Unidade Peso Objeto: kg; Definição de Orientação Janela: 0; Operação IFC (ifc_optypestr): Outro; Operação IFC (ifc_optype): 10; Ângulo de Abertura Veneziana: 180 deg
ArchiCADProperties - Dimensões do Requadro: 1,00×1,20; Dimensões do Vão: 1,00×1,20; Dimensões da Unidade: 1,00×1,20; Tamanho Nominal L x A: 1,00×1,20; Tamanho Nominal L x A X E: 1,00×1,20×0,15; Estrutura da Parede: Alvenaria 140, Rebocada 2 Faces; Texto Marcador: <Texto Personal.>; Nome Item de Biblioteca Abertura: Janela de Correr 3-Caixilhos 27; Índice da Trama Lateral da Abertura: Trama Vazia; Vegetal: ARQ - Parede; Nome de Item de Biblioteca: Janela de Correr 3-Caixilhos 27; Material de Construção/ Composição / Perfil / Trama: Trama Vazia; Tipo de Trama: Trama Vazia; Protegido: no; Nome Piso de Origem: Pavimento Térreo; Número Piso de Origem: 0; Tipo de Elemento: Janela; Superfícies (Todas): Metal - Aço Inoxidável; Vidro - Simples; Nome das Opções de Projeto: Modelo Principal; Nome do Conjunto de Opções de Projeto: Modelo Principal; Posição: Exterior; Mostrar em Filtro de Renovação: Todos os Filtros Relevantes; Função Estrutural: Elemento Não-Estrutural; Estado de Renovação: Existente; Estado das Opções de Projeto: Modelo Principal; Conjunto de Opções de Projeto: Modelo Principal
AC_Pset_RenovationAndPhasing - Renovation Status: Existing
BaseQuantities - GrossArea: 1.2 m2; Height: 1200 mm; Width: 1000 mm; Perimeter: 4400 mm; Area: 1.2 m2; Volume: 0.0543 m3; Depth: 150 mm; NetVolume: 0.0543 m3
AC_Equantity_Janela_de_Correr_3-Caixilhos_27 - Largura: 1000 mm; Altura: 1200 mm; Dimensão Z: 1000 mm; Nível da Base: 1000 mm; Nível do Topo: 0 mm; Altura Peitoril ao Piso Atual: 1000 mm; Abertura para o Núcleo da Parede: 0 mm; Nova Largura Direita da Trama de Parede: 150 mm; Nova Largura Esquerda da Trama de Parede: 150 mm; Espessura Parede Ligação: 0 mm; Espessura Parede 2 Conectada: 150 mm; Espessura Parede 1 Conectada: 150 mm; Largura Pilar de Canto: 0 mm; Espessura Pilar Canto: 0 mm; Projeção Pilar de Canto: 0 mm; Tolerância Máxima: 100 mm; Tolerância: 0 mm; Tolerância Esquerda: 0 mm; Tolerância Direita: 0 mm; Tolerância Superior: 0 mm; Tolerância Inferior: 0 mm; Largura de Vão: 1000 mm; Altura de Vão: 1200 mm; Largura Face de Vão: 1000 mm; Altura Face de Vão: 1200 mm; Largura Unidade: 1000 mm; Altura Unidade: 1200 mm; Espessura Batente: 100 mm; Largura Batente: 50 mm; Largura Batente Lado 2: 50 mm; Largura Batente Cimo: 50 mm; Largura Batente Base: 50 mm; Profundidade Rebaixo: 25 mm; Largura Rebaixo: 25 mm; Largura Divisão Superior: 100 mm; Altura Divisões Sup. Horiz.: 1040 mm; Largura Montante: 100 mm; Tamanho Caixilho Lado: 333.333 mm; Tamanho caixilho Meio (sashWidth2): 333.333 mm; Tamanho caixilho Meio (tempSashWidth2): 358.333 mm; Espessura Estrutura Caixilho: 50 mm; Largura Caixilho: 50 mm; Largura Grelha: 20 mm; Espessura Grelha: 25 mm; Altura Saliência: 400 mm; Espessura Saliência: 50 mm; Espessura Vidro: 20 mm; Altura Maçaneta: 600 mm; Posição Maçaneta: 25 mm; Sobred. Abertura Esquerda: 0 mm; Sobred. Direita Abertura: 0 mm; Sobred. Topo Abertura: 0 mm; Sobred. Base Abertura: 0 mm; Largura Arquitrave Principal: 20 mm; Largura Lado 1 (gs_tw_right_out): 100 mm; Largura Lado 2 (gs_tw_left_out): 100 mm; Largura Topo (gs_tw_top_out): 100 mm; Largura Inferior (gs_tw_bottom_out): 100 mm; Espessura de Parede (gs_trim_thk_out): 25 mm; Espessura na Abertura da Parede (gs_trim_width_out): 25 mm; Paralelas (gs_trim_offs_out): 0 mm; Bordo (gs_trim_jambext_nosing_out): 50 mm; Saliência Superior (gs_trimov_top_left_out): 100 mm; Saliência Superior (gs_trimov_top_right_out): 100 mm; Ressalto Inferior (gs_trimov_bot_left_out): 100 mm; Ressalto Inferior (gs_trimov_bot_right_out): 100 mm; Ressalto Inferior (casingOverhangBottomSideOut): 50 mm; Largura Lado 1 (gs_tw_right_in): 100 mm; Largura Lado 2 (gs_tw_left_in): 100 mm; Largura Topo (gs_tw_top_in): 100 mm; Largura Inferior (gs_tw_bottom_in): 100 mm; Espessura de Parede (gs_trim_thk_in): 25 mm; Espessura na Abertura da Parede (gs_trim_width_in): 25 mm; Paralelas (gs_trim_offs_in): 0 mm; Bordo (gs_trim_jambext_nosing_in): 50 mm; Saliência Superior (gs_trimov_top_left_in): 100 mm; Saliência Superior (gs_trimov_top_right_in): 100 mm; Ressalto Inferior (gs_trimov_bot_left_in): 100 mm; Ressalto Inferior (gs_trimov_bot_right_in): 100 mm; Largura Peitoril: 0 mm; Largura Topo Parapeito: 10 mm; Altura Topo Peitoril: 10 mm; Espessura Peitoril: 25 mm; Espessura Lateral da Frente Peitoril: 15 mm; Elevação Peitoril: 5 mm; Recobrimento Goteira Peitoril: 20 mm; Largura Goteira Peitoril: 30 mm; Testeira Peitoril: 30 mm; Avanço do Parapeito Esquerda: 0 mm; Avanço do Parapeito Direita: 0 mm; Inclinação do Parapeito: 20 mm; Inclin. Peitoril da Parede: 0 mm; Profund. Vão Posterior (gs_sill_holeDepthBehind): 0 mm; Espessura do Tijolo (gs_brick_sill_br_thk): 65 mm; Espessura de Argamassa (gs_brick_sill_mort_thk): 15 mm; Largura Peitoril Int.: 80 mm; Espessura Peitoril Int.: 25 mm; Peitoril Int. Arredondado: 30 mm; Saliência Esq. Peitoril Int.: 0 mm; Saliência Dir. Peitoril Int.: 0 mm; Inclinação do Parapeito Int.: 0 mm; Altura Perfil: 65 mm; Espessura Perfil: 110 mm; Altura Painel: 1500 mm; Afast. Interior: 20 mm; Profund. Fechamento: 0 mm; Largura Batente Extra: 40 mm; Espess. Batente Extra: 30 mm; Largura Barra:: 30 mm; Comprim. Vara Suspensa: 20 mm; Raio Vara Suspensa: 5 mm; Distância Painel: 6 mm; Saliência Exterior: 0 mm; Largura Painel Interior: 120 mm; Comprim. Abertura 3D: 1500 mm; Comprim. Fechado 3D: 0 mm; Comprimento 1 Abertura 3D (gs_shutter_opLength_1): 560 mm; Comprimento 1 Abertura 3D (gs_shutter_opLength_2): 140 mm; Altura Abertura 3D: 1500 mm; Altura Fechado 3D: 0 mm; Espessura Painel: 50 mm; Largura Estrutura Painel: 50 mm; Largura Moldura Inferior: 50 mm; Largura Painel: 0 mm; Espess. de Enchimento de Painel: 10 mm; Espessura da Veneziana: 10 mm; Largura Grelha Ventilação: 40 mm; Largura Divisor Moldura Horiz.: 50 mm; Largura de Divisor Moldura Vert.: 50 mm; Raio do Vão: 10 mm; Largura Bordo Vertical: 100 mm; Largura Estrutura Z: 50 mm; Espessura Estrutura Z: 25 mm; Espess. Placas Verticais: 25 mm; Espess. Placas Horizontais: 25 mm; Largura Aprox. Placas Verticais: 80 mm; Largura Aprox. Placas Horizontais: 115 mm; Altura Caixa (gs_shutRoll_boxHeight): 200 mm; Profund. Caixa (gs_shutRoll_boxWidth): 150 mm; Afast. Caixa Esq.: 0 mm; Afast. Caixa Dir.: 0 mm; Profund. Anteparos: 72.5 mm; Distância da Parede (gs_shutRoll_distFromWall): 0 mm; Distância da Padieira (gs_shutRoll_distFromHead): 0 mm; Largura da Ripa: 50 mm; Altura Caixa (gs_shutLam_boxHeight): 200 mm; Profund. Caixa (gs_shutLam_boxWidth): 150 mm; Largura Capa: 0 mm; Distância da Parede (gs_shutLam_distFromWall): 0 mm; Distância da Padieira (gs_shutLam_distFromHead): 0 mm; Largura Segmento (gs_shutLam_segmentWidth): 60 mm; Altura Caixa (gs_shutLam2_boxHeight): 60 mm; Largura Caixa: 60 mm; Distância da Janela: 60 mm; Distância da Padieira (gs_shutLam2_distFromHead): 60 mm; Altura do Eixo da Caixa da Padieira: 0 mm; Largura Segmento (gs_shutLam2_segmentWidth): 60 mm; Distância entre Arco e Janela: 0 mm; Avanço à Esquerda do Arco de Alvenaria: 0 mm; Avanço à Direita do Arco de Alvenaria: 0 mm; Espelho do Arco de Alvenaria: 30 mm; Projeção do Arco de Alvenaria: 0 mm; Altura do Arco de Alvenaria: 250 mm; Profundidade do Arco de Alvenaria: 120 mm; Profund. Vão Posterior (gs_masonry_arch_rearHoleDepth): 0 mm; Espessura do Tijolo (gs_masonry_arch_brick_thk): 65 mm; Espessura de Argamassa (gs_masonry_arch_mort_thk): 10 mm; Largura Fecho: 100 mm; Sobredimensão Fecho: 0 mm; Projeção Fecho: 10 mm; Profund. Face de Vão (gs_wido_sill): 0 mm; Profund. Face de Vão (AC_wido_sill): 0 mm; Profund. Ombreira Lado 2: 60 mm; Profund. Ombreira: 60 mm; Profund. Ombreira Interior Lado 2 (gs_reveal_splayed_innerLeft): 60 mm; Profund. Ombreira Interior (gs_reveal_splayed_innerRight): 60 mm; Profund. Ombreira Interior Lado 2 (gs_reveal_double_innerLeft): 60 mm; Profund. Ombreira Interior (gs_reveal_double_innerRight): 60 mm; Profund. Batente Cima: 60 mm; Profund. Batente Peitoril: 60 mm; Profundidade Padieira Interior (gs_reveal_splayed_innerTop): 60 mm; Profundidade Peitoril Interior (gs_reveal_splayed_innerBottom): 60 mm; Profundidade Padieira Interior (gs_reveal_double_innerTop): 60 mm; Profundidade Peitoril Interior (gs_reveal_double_innerBottom): 60 mm; Profund. Batente Exterior: 80 mm; Limite Espess. Reboco: 40 mm; Distância de Camada do Encerram.: 0 mm; Largura do Fecho: 38 mm; Espessura do Fecho: 100 mm; Espessura da Camada: 25 mm; Espessura do Perfil: 75 mm; Espessura Personal.: 15 mm; Saliência Camada para Espess. Batente: 0 mm; Profundidade do Recorte: 50 mm; Largura de Parapeito: 1000 mm; Avanço Lateral 1: 0 mm; Avanço Lateral 2: 0 mm; Altura Parapeito: 900 mm; Ressalto Inferior (gs_parapet_botelev): 0 mm; Largura Abertura 3D Caixilho Meio: 0 mm; Largura de Vão 3D Caixilho Principal Lado 2: 0 mm; Largura Abertura 3D Caixilho Lado 1: 0 mm; Largura Abertura 3D Caixilho Lado 2: 0 mm; Largura Abertura 2D Caixilho Meio: 0 mm; Largura Abertura 2D Caixilho Lado 1: 0 mm; Largura Abertura 2D Caixilho Lado 2: 0 mm; Sobred. Abertura Esq. AC: 0 mm; Sobred. Abertura Dir. AC: 0 mm; Sobred. Padieira AC: 0 mm; Sobred. Abertura Base AC: 0 mm
Component Quantities - Component, Volume Componente (Líquido): 0.0543 m3; Component, Volume do componente (Bruto): 0.0543 m3
ArchiCADQuantities - Abertura Volume de Vão L/D: 0.18 m3; P/J Volume Nominal da Abertura: 0.18 m3; Abertura Área da Superfície L/D: 4.61213 m2; P/J Área de Superfície Nominal do Vão: 1.2 m2; P/J Largura do Vão no Lado Oposto do Requadro: 1000 mm; P/J Altura do Vão no Lado Oposto do Requadro: 1200 mm; P/J Largura do Vão no Lado do Requadro: 1000 mm; P/J Altura do Vão no Lado do Requadro: 1200 mm; Área da Superfície da Abertura no Lado do Requadro da J/P: 1.2 m2; Área da Superfície da Abertura no Lado Oposto ao Requadro da J/P: 1.2 m2; P/J Largura do Vão Nominal no Lado Oposto do Requadro: 1000 mm; P/J Altura do Vão Nominal no Lado Oposto do Requadro: 1200 mm; P/J Largura do Vão Nominal no Lado do Requadro: 1000 mm; P/J Altura do Vão Nominal no Lado do Requadro: 1200 mm; P/J Área da Superfície do Vão Nominal no Lado do Requadro: 1.2 m2; P/J Área da Superfície do Vão Nominal no Lado Oposto do Requadro: 1.2 m2; Altura da Soleira/Peitoril ou Padieira: 1000 mm; P/J Altura Nominal do Parapeito: 1000 mm; P/J Altura do Parapeito no Lado do Requadro: 1000 mm; P/J Altura do Parapeito no Lado Oposto do Requadro: 1000 mm; P/J Altura Nominal da Padieira: 2200 mm; P/J Altura da Padiera no Lado Oposto do Requadro: 2200 mm; P/J Altura da Padiera no Lado do Requadro: 2200 mm; Espessura da Parede: 150 mm; Espessura do Batente: 100 mm; Altura: 1200 mm; Volume (Líquido): 0.0543 m3; Largura: 1000 mm; Elevação à Origem do Projeto: 1000 mm; Elevação ao 1º Nível de Referência: 1000 mm; Elevação ao 2º Nível de Referência: 1000 mm; Elevação ao Nível do Mar: 1000 mm; Elevação ao Piso: 1000 mm; Afastamento do Piso de Origem: 1000 mm; Área da Superfície: 4.61213 m2; Elevação do Topo ao Primeiro Nível de Referência: 2200 mm; Elevação do Topo Ao Piso de Origem: 2200 mm; Elevação do Topo À Cota Zero: 2200 mm; Elevação do Topo Ao Nível do Mar: 2200 mm; Elevação do Topo Ao Segundo Nível de Referência: 2200 mm; Elevação da Base Ao Primeiro Nível de Referência: 1000 mm; Elevação da Base Ao Piso de Origem: 1000 mm; Elevação da Base À Cota Zero: 1000 mm; Elevação da Base Ao Nível do Mar: 1000 mm; Elevação da Base Ao Segundo Nível de Referência: 1000 mm; Área da Superfície da Base (Líquida): 4.61213 m2
Name | Selecione Caixilho | ID do Elemento = ID do Elemento e Associação | Nome da Zona Relacionada = Da Zona | Número da Zona Relacionada = Do Número de Zona | ID Pai
J03 | 1 | J03 | Dormitório 1 | 01 | Parede-01
J05 | 4 | J05 | Dormitório 3 | 02 | Parede-02
J04 | 4 | J04 | Dormitório 2 | 02 | Parede-02
